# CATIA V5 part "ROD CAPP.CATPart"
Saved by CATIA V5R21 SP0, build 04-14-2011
Part number: Part4
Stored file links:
  G:\CATIA\PROJECT__01\ROD CAPP.CATPart

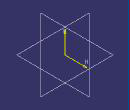
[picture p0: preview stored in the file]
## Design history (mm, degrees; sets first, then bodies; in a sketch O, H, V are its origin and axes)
Body1 (main body)
  Sketch1 on yz-plane, origin (0, 0, 0), H (0, 1, 0), V (0, 0, 1)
